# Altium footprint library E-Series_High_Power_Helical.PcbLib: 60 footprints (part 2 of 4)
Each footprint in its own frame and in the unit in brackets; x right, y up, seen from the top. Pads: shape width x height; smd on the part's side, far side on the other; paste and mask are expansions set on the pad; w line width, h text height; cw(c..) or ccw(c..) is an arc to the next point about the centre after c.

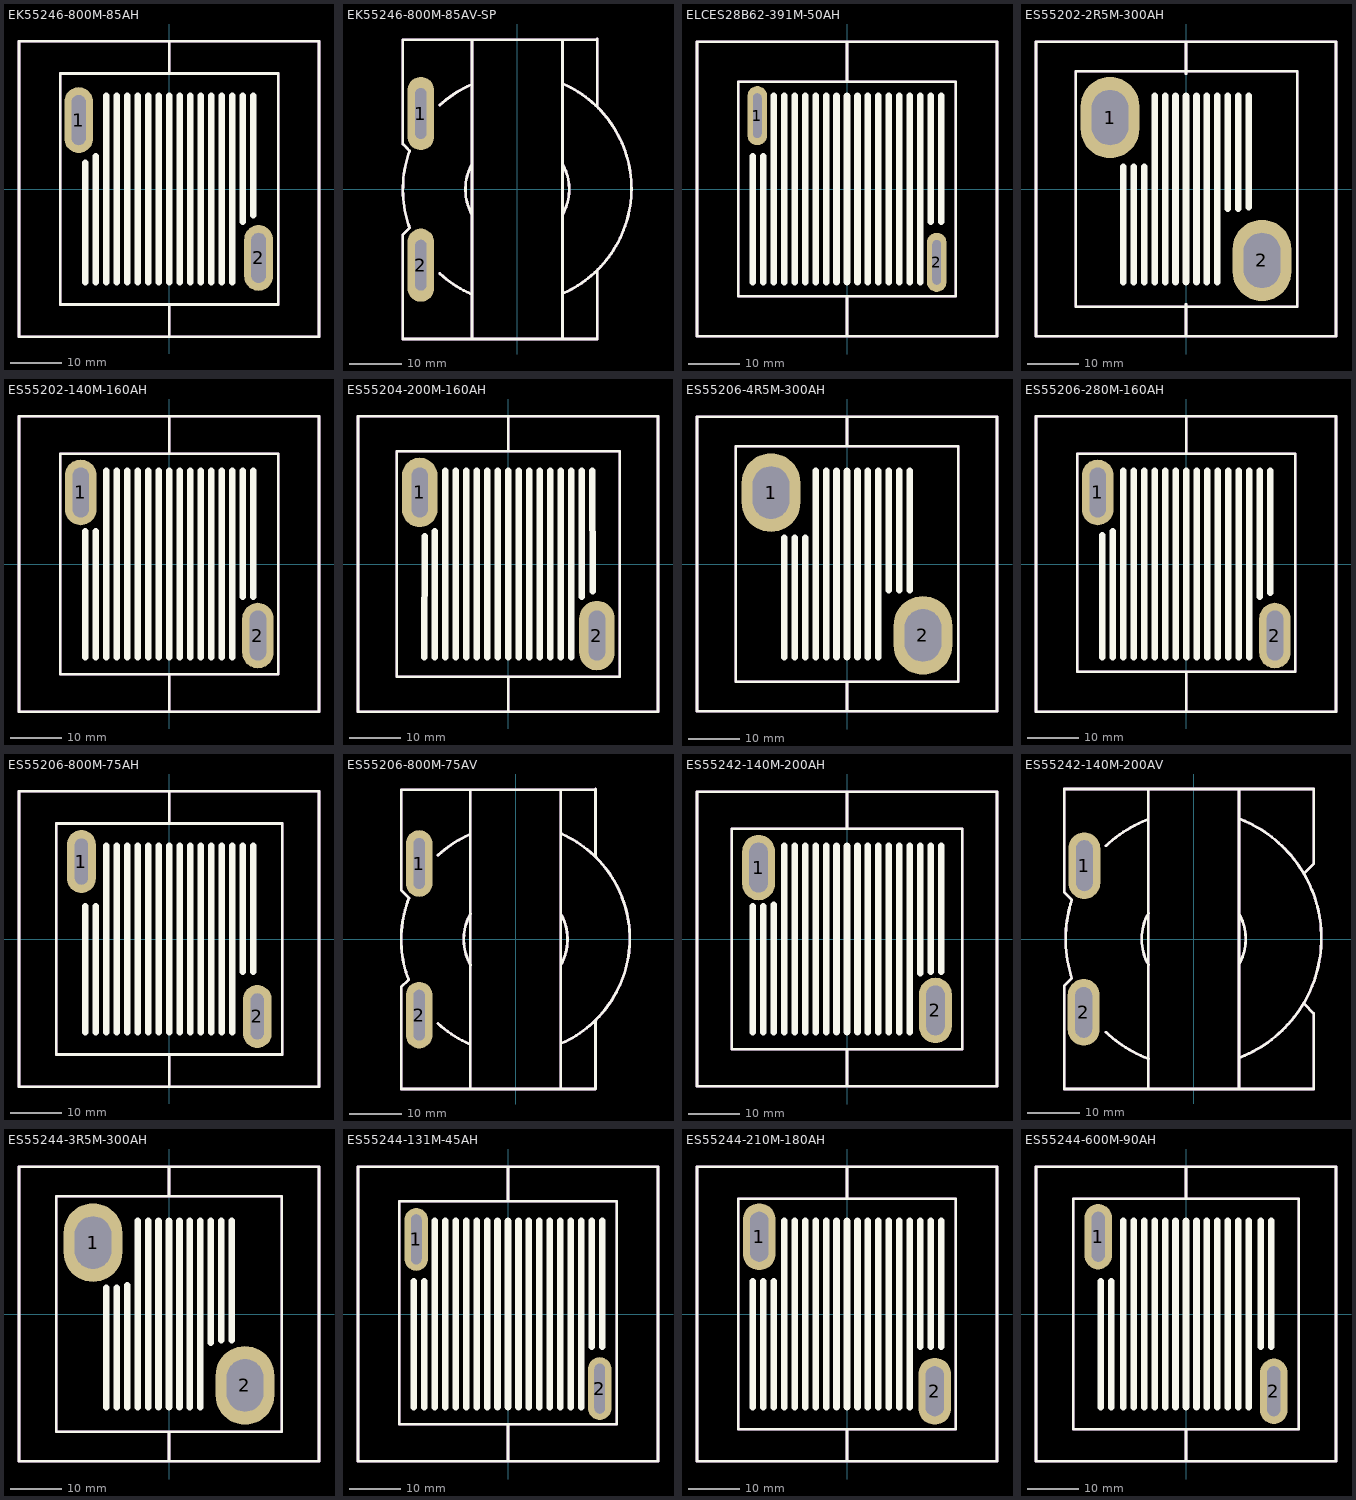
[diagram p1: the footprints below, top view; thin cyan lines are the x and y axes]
## EK55246-800M-85AH [mil]
pads (2):
  oval 220x500 hole 110 slot 380 at 90 deg: 1(-690,525) 2(680,-525)
Top Overlay:
  lines w19.68: 0,-1120 0,-880 ; 0,880 0,1120 ; -1145,-1125 1140,-1125 1140,1125 -1145,1125 -1145,-1125 ; -830,-880 -830,880 830,880 830,-880 -830,-880
  lines w50: -640,-710 -640,200 ; -560,-710 -560,250 ; -480,-710 -480,710 ; -400,-710 -400,710 ; -320,-710 -320,710 ; -240,-710 -240,710 ; -160,-710 -160,710 ; -80,-710 -80,710 ; 0,-710 0,710 ; 80,-710 80,710 ; 160,-710 160,710 ; 240,-710 240,710 ; 320,-710 320,710 ; 400,-710 400,710 ; 480,-710 480,710 ; 560,-250 560,710 ; 640,-200 640,710
Components Top Assy:
  lines w19.68: 0,-1120 0,-880 ; 0,880 0,1120 ; -1145,-1125 1140,-1125 1140,1125 -1145,1125 -1145,-1125 ; -830,-880 -830,880 830,880 830,-880 -830,-880
  text "'.Designator'" at -938.15,-44.83 h400

## EK55246-800M-85AV-SP [mil]
pads (2):
  oval 200x550 hole 85 slot 380 at 90 deg: 1(-725,570) 2(-725,-570)
Top Overlay:
  lines w19.68: -810,-290 -860,-340 -860,-1125 600,-1125 ; -810,290 -830,310 -860,340 -860,1125 590,1125
  lines w20: -813.86,-277.9 cw(c0,0) -809.67,289.88 ; -583.48,-632.1 ccw(c0,0) -344.8,-788.11 ; -583.48,632.1 cw(c0,0) -344.8,788.11 ; -340,-1120 -340,1110 ; -338.61,-193.49 cw(c0,0) -338.61,193.49 ; 338.61,-193.49 ccw(c0,0) 338.61,193.49 ; 340,-1110 340,1120 ; 342.28,-782.35 ccw(c-2.13,5.68) 346.4,791.89 ; 600,-1120 600,-608.95 ; 600,620 600,1130
Components Top Assy:
  lines w19.68: -810,-290 -860,-340 -860,-1125 600,-1125 ; -810,290 -830,310 -860,340 -860,1125 590,1125
  lines w20: -813.86,-277.9 cw(c0,0) -809.67,289.88 ; -583.48,-632.1 ccw(c0,0) -344.8,-788.11 ; -583.48,632.1 cw(c0,0) -344.8,788.11 ; -340,-1120 -340,1110 ; -338.61,-193.49 cw(c0,0) -338.61,193.49 ; 338.61,-193.49 ccw(c0,0) 338.61,193.49 ; 340,-1110 340,1120 ; 342.28,-782.35 ccw(c-2.13,5.68) 346.4,791.89 ; 600,-1120 600,-608.95 ; 600,620 600,1130
  text "'.Designator'" at -968.15,-74.83 h400

## ELCES28B62-391M-50AH [mil]
pads (2):
  oval 150x450 hole 65 slot 340 at 90 deg: 1(-685,560) 2(685,-560)
Top Overlay:
  lines w19.68: 0,-1120 0,-820 ; 0,820 0,1120 ; -1145,-1125 -1145,1125 1145,1125 1145,-1125 -1145,-1125 ; -830,-820 -830,820 830,820 830,-820 -830,-820
  lines w50: -720,-710 -720,250 ; -640,-710 -640,250 ; -560,-710 -560,710 ; -480,-710 -480,710 ; -400,-710 -400,710 ; -320,-710 -320,710 ; -240,-710 -240,710 ; -160,-710 -160,710 ; -80,-710 -80,710 ; 0,-710 0,710 ; 80,-710 80,710 ; 160,-710 160,710 ; 240,-710 240,710 ; 320,-710 320,710 ; 400,-710 400,710 ; 480,-710 480,710 ; 560,-710 560,710 ; 640,-250 640,710 ; 720,-250 720,710
Components Top Assy:
  lines w19.68: 0,-1120 0,-820 ; 0,820 0,1120 ; -1145,-1125 -1145,1125 1145,1125 1145,-1125 -1145,-1125 ; -830,-820 -830,820 830,820 830,-820 -830,-820
  text "'.Designator'" at -938.15,-44.83 h400

## ES55202-2R5M-300AH [mil]
pads (2):
  oval 450x620 hole 280 slot 420 at 90 deg: 1(-580,545) 2(580,-545)
Top Overlay:
  lines w19.68: 0,-1120 0,-880 ; 0,880 0,1120 ; -1145,-1125 -1145,1125 1145,1125 1145,-1125 -1145,-1125 ; -840,-900 -840,900 850,900 850,-900 -840,-900
  lines w50: -480,-710 -480,170 ; -400,-710 -400,170 ; -320,-710 -320,170 ; -240,-710 -240,710 ; -160,-710 -160,710 ; -80,-710 -80,710 ; 0,-710 0,710 ; 80,-710 80,710 ; 160,-710 160,710 ; 240,-710 240,710 ; 320,-150 320,710 ; 400,-150 400,710 ; 480,-140 480,710
Components Top Assy:
  lines w19.68: 0,-1120 0,-880 ; 0,880 0,1120 ; -1145,-1125 -1145,1125 1145,1125 1145,-1125 -1145,-1125 ; -840,-900 -840,900 850,900 850,-900 -840,-900
  text "'.Designator'" at -938.15,-44.83 h400

## ES55202-140M-160AH [mil]
pads (2):
  oval 240x500 hole 125 slot 380 at 90 deg: 1(-675,545) 2(675,-545)
Top Overlay:
  lines w19.68: 0,-1120 0,-840 ; 0,840 0,1120 ; -1145,-1125 -1145,1125 1140,1125 1140,-1125 -1145,-1125 ; -830,-840 -830,840 830,840 830,-840 -830,-840
  lines w50: -640,-710 -640,250 ; -560,-710 -560,250 ; -480,-710 -480,710 ; -400,-710 -400,710 ; -320,-710 -320,710 ; -240,-710 -240,710 ; -160,-710 -160,710 ; -80,-710 -80,710 ; 0,-710 0,710 ; 80,-710 80,710 ; 160,-710 160,710 ; 240,-710 240,710 ; 320,-710 320,710 ; 400,-710 400,710 ; 480,-710 480,710 ; 560,-250 560,710 ; 640,-250 640,710
Components Top Assy:
  lines w19.68: 0,-1120 0,-840 ; 0,840 0,1120 ; -1145,-1125 -1145,1125 1140,1125 1140,-1125 -1145,-1125 ; -830,-840 -830,840 830,840 830,-840 -830,-840
  text "'.Designator'" at -938.15,-44.83 h400

## ES55204-200M-160AH [mil]
pads (2):
  oval 270x530 hole 125 slot 380 at 90 deg: 1(-675,545) 2(675,-545)
Top Overlay:
  lines w19.68: 0,-1120 0,-860 ; 0,860 0,1120 ; -1145,-1125 -1145,1125 1140,1125 1140,-1125 -1145,-1125 ; -850,-860 -850,860 850,860 850,-860 -850,-860
  lines w50: -640,-710 -635,211 ; -560,-710 -560,250 ; -480,-710 -480,710 ; -400,-710 -400,710 ; -320,-710 -320,710 ; -240,-710 -240,710 ; -160,-710 -160,710 ; -80,-710 -80,710 ; 0,-710 0,710 ; 80,-710 80,710 ; 160,-710 160,710 ; 240,-710 240,710 ; 320,-710 320,710 ; 400,-710 400,710 ; 480,-710 480,710 ; 560,-250 560,710 ; 640,710 642,-209
Components Top Assy:
  lines w19.68: 0,-1120 0,-860 ; 0,860 0,1120 ; -1145,-1125 -1145,1125 1140,1125 1140,-1125 -1145,-1125 ; -850,-860 -850,860 850,860 850,-860 -850,-860
  text "'.Designator'" at -948.15,-44.83 h400

## ES55206-4R5M-300AH [mil]
pads (2):
  oval 450x600 hole 280 slot 400 at 90 deg: 1(-580,545) 2(580,-545)
Top Overlay:
  lines w19.68: 0,-1120 0,-900 ; 0,900 0,1120 ; -1145,-1125 -1145,1125 1145,1125 1145,-1125 -1145,-1125 ; -850,-900 -850,900 850,900 850,-900 -850,-900
  lines w50: -480,-710 -480,200 ; -400,-710 -400,200 ; -320,-710 -320,200 ; -240,-710 -240,710 ; -160,-710 -160,710 ; -80,-710 -80,710 ; 0,-710 0,710 ; 80,-710 80,710 ; 160,-710 160,710 ; 240,-710 240,710 ; 320,-200 320,710 ; 400,-200 400,710 ; 480,-200 480,710
Components Top Assy:
  lines w19.68: 0,-1120 0,-900 ; 0,900 0,1120 ; -1145,-1125 -1145,1125 1145,1125 1145,-1125 -1145,-1125 ; -850,-900 -850,900 850,900 850,-900 -850,-900
  text "'.Designator'" at -928.15,-104.83 h400

## ES55206-280M-160AH [mil]
pads (2):
  oval 240x500 hole 125 slot 380 at 90 deg: 1(-675,545) 2(675,-545)
Top Overlay:
  lines w19.68: 0,-1120 0,-820 ; 0,840 0,1120 ; -1145,-1125 1140,-1125 1140,1125 -1145,1125 -1145,-1125 ; -830,-820 830,-820 830,840 -830,840 -830,-820
  lines w50: -640,-710 -640,220 ; -560,-710 -560,250 ; -480,-710 -480,710 ; -400,-710 -400,710 ; -320,-710 -320,710 ; -240,-710 -240,710 ; -160,-710 -160,710 ; -80,-710 -80,710 ; 0,-710 0,710 ; 80,-710 80,710 ; 160,-710 160,710 ; 240,-710 240,710 ; 320,-710 320,710 ; 400,-710 400,710 ; 480,-710 480,710 ; 560,-250 560,710 ; 640,-220 640,710
Components Top Assy:
  lines w19.68: 0,-1120 0,-820 ; 0,840 0,1120 ; -1145,-1125 1140,-1125 1140,1125 -1145,1125 -1145,-1125 ; -830,-820 830,-820 830,840 -830,840 -830,-820
  text "'.Designator'" at -938.15,-44.83 h400

## ES55206-800M-75AH [mil]
pads (2):
  oval 220x480 hole 100 slot 350 at 90 deg: 1(-670,590) 2(670,-590)
Top Overlay:
  lines w19.68: 0,-1120 0,-880 ; 0,880 0,1120 ; -1145,-1125 -1145,1125 1140,1125 1140,-1125 -1145,-1125 ; -860,-880 860,-880 860,880 -860,880 -860,-880
  lines w50: -640,-710 -640,250 ; -560,-710 -560,250 ; -480,-710 -480,710 ; -400,-710 -400,710 ; -320,-710 -320,710 ; -240,-710 -240,710 ; -160,-710 -160,710 ; -80,-710 -80,710 ; 0,-710 0,710 ; 80,-710 80,710 ; 160,-710 160,710 ; 240,-710 240,710 ; 320,-710 320,710 ; 400,-710 400,710 ; 480,-710 480,710 ; 560,-250 560,710 ; 640,-250 640,710
Components Top Assy:
  lines w19.68: 0,-1120 0,-880 ; 0,880 0,1120 ; -1145,-1125 -1145,1125 1140,1125 1140,-1125 -1145,-1125 ; -860,-880 860,-880 860,880 -860,880 -860,-880
  text "'.Designator'" at -938.15,-44.83 h400

## ES55206-800M-75AV [mil]
pads (2):
  oval 200x500 hole 85 slot 380 at 90 deg: 1(-725,570) 2(-725,-570)
Top Overlay:
  lines w19.68: -804.35,-304.35 -860,-360 -860,-1125 600,-1125 ; -800,310 -860,370 -860,1125 590,1125
  lines w20: -804.35,-304.35 cw(c0,0) -801.9,310.74 ; -583.48,-632.1 ccw(c0,0) -344.8,-788.11 ; -583.48,632.1 cw(c0,0) -344.8,788.11 ; -340,-1120 -340,1110 ; -338.61,-193.49 cw(c0,0) -338.61,193.49 ; 338.61,-193.49 ccw(c0,0) 338.61,193.49 ; 340,-1110 340,1120 ; 342.28,-782.35 ccw(c-2.13,5.68) 346.4,791.89 ; 600,-1120 600,-608.95 ; 600,620 600,1130
Components Top Assy:
  lines w19.68: -804.35,-304.35 -860,-360 -860,-1125 600,-1125 ; -800,310 -860,370 -860,1125 590,1125
  lines w20: -804.35,-304.35 cw(c0,0) -801.9,310.74 ; -583.48,-632.1 ccw(c0,0) -344.8,-788.11 ; -583.48,632.1 cw(c0,0) -344.8,788.11 ; -340,-1120 -340,1110 ; -338.61,-193.49 cw(c0,0) -338.61,193.49 ; 338.61,-193.49 ccw(c0,0) 338.61,193.49 ; 340,-1110 340,1120 ; 342.28,-782.35 ccw(c-2.13,5.68) 346.4,791.89 ; 600,-1120 600,-608.95 ; 600,620 600,1130
  text "'.Designator'" at -968.15,-74.83 h400

## ES55242-140M-200AH [mil]
pads (2):
  oval 250x500 hole 140 slot 380 at 90 deg: 1(-675,545) 2(675,-545)
Top Overlay:
  lines w19.68: 0,-1120 0,-840 ; 0,840 0,1120 ; -1145,-1125 -1145,1125 1145,1125 1145,-1125 -1145,-1125 ; -880,-840 -880,840 880,840 880,-840 -880,-840
  lines w50: -720,-710 -720,250 ; -640,-710 -640,250 ; -560,-710 -560,260 ; -480,-710 -480,710 ; -400,-710 -400,710 ; -320,-710 -320,710 ; -240,-710 -240,710 ; -160,-710 -160,710 ; -80,-710 -80,710 ; 0,-710 0,710 ; 80,-710 80,710 ; 160,-710 160,710 ; 240,-710 240,710 ; 320,-710 320,710 ; 400,-710 400,710 ; 480,-710 480,710 ; 560,-260 560,710 ; 640,-250 640,710 ; 720,-250 720,710
Components Top Assy:
  lines w19.68: 0,-1120 0,-840 ; 0,840 0,1120 ; -1145,-1125 -1145,1125 1145,1125 1145,-1125 -1145,-1125 ; -880,-840 -880,840 880,840 880,-840 -880,-840
  text "'.Designator'" at -938.15,-44.83 h400

## ES55242-140M-200AV [mil]
pads (2):
  oval 240x500 hole 125 slot 380 at 90 deg: 1(-820,550) 2(-825,-550)
Top Overlay:
  lines w19.68: -915,-295 -970,-350 -970,-1125 900,-1125 ; -914.08,294.08 -970,350 -970,1125 900,1125
  lines w20: -917.16,-283.58 cw(c0,0) -913.74,294.43 ; -658.87,698.21 cw(c0,0) -347.95,894.72 ; -658.27,-698.77 ccw(c0,0) -339.26,-898.05 ; -340,-1120 -340,1110 ; -338.61,-193.49 cw(c0,0) -338.61,193.49 ; 338.61,-193.49 ccw(c0,0) 338.61,193.49 ; 340,-1110 340,1120 ; 352.55,-886.4 ccw(c-2.13,5.68) 353.01,897.57 ; 830,-488.75 900,-558.75 900,-1120 ; 830,493.75 900,563.75 900,1125
Components Top Assy:
  lines w19.68: -915,-295 -970,-350 -970,-1125 900,-1125 ; -914.08,294.08 -970,350 -970,1125 900,1125
  lines w20: -917.16,-283.58 cw(c0,0) -913.74,294.43 ; -658.87,698.21 cw(c0,0) -347.95,894.72 ; -658.27,-698.77 ccw(c0,0) -339.26,-898.05 ; -340,-1120 -340,1110 ; -338.61,-193.49 cw(c0,0) -338.61,193.49 ; 338.61,-193.49 ccw(c0,0) 338.61,193.49 ; 340,-1110 340,1120 ; 352.55,-886.4 ccw(c-2.13,5.68) 353.01,897.57 ; 830,-488.75 900,-558.75 900,-1120 ; 830,493.75 900,563.75 900,1125
  text "'.Designator'" at -918.15,-54.83 h400

## ES55244-3R5M-300AH [mil]
pads (2):
  oval 450x600 hole 280 slot 400 at 90 deg: 1(-580,545) 2(580,-545)
Top Overlay:
  lines w19.68: 0,-1125 0,-900 ; 0,900 0,1120 ; -1145,-1125 1145,-1125 1145,1125 -1145,1125 -1145,-1125 ; -860,-900 860,-900 860,900 -860,900 -860,-900
  lines w50: -480,-710 -480,200 ; -400,-710 -400,200 ; -320,-710 -320,220 ; -240,-710 -240,710 ; -160,-710 -160,710 ; -80,-710 -80,710 ; 0,-710 0,710 ; 80,-710 80,710 ; 160,-710 160,710 ; 240,-710 240,710 ; 320,-220 320,710 ; 400,-200 400,710 ; 480,-200 480,710
Components Top Assy:
  lines w19.68: 0,-1120 0,-900 ; 0,900 0,1120 ; -1145,-1125 1145,-1125 1145,1125 -1145,1125 -1145,-1125 ; -860,-900 860,-900 860,900 -860,900 -860,-900
  text "'.Designator'" at -938.15,-44.83 h400

## ES55244-131M-45AH [mil]
pads (2):
  oval 180x480 hole 80 slot 380 at 90 deg: 1(-700,570) 2(700,-570)
Top Overlay:
  lines w19.68: 0,-1120 0,-840 ; 0,860 0,1120 ; -1145,-1125 -1145,1125 1145,1125 1145,-1125 -1145,-1125 ; -830,-840 -830,860 830,860 830,-840 -830,-840
  lines w50: -720,-710 -720,250 ; -640,-710 -640,250 ; -560,-710 -560,710 ; -480,-710 -480,710 ; -400,-710 -400,710 ; -320,-710 -320,710 ; -240,-710 -240,710 ; -160,-710 -160,710 ; -80,-710 -80,710 ; 0,-710 0,710 ; 80,-710 80,710 ; 160,-710 160,710 ; 240,-710 240,710 ; 320,-710 320,710 ; 400,-710 400,710 ; 480,-710 480,710 ; 560,-710 560,710 ; 640,-250 640,710 ; 720,-250 720,710
Components Top Assy:
  lines w19.68: 0,-1120 0,-840 ; 0,860 0,1120 ; -1145,-1125 -1145,1125 1145,1125 1145,-1125 -1145,-1125 ; -830,-840 -830,860 830,860 830,-840 -830,-840
  text "'.Designator'" at -938.15,-44.83 h400

## ES55244-210M-180AH [mil]
pads (2):
  oval 250x510 hole 140 slot 380 at 90 deg: 1(-670,590) 2(670,-590)
Top Overlay:
  lines w19.68: 0,-1120 0,-880 ; 0,880 0,1120 ; -1145,-1125 -1145,1125 1145,1125 1145,-1125 -1145,-1125 ; -830,-880 -830,880 830,880 830,-880 -830,-880
  lines w50: -720,-710 -720,250 ; -640,-710 -640,250 ; -560,-710 -560,250 ; -480,-710 -480,710 ; -400,-710 -400,710 ; -320,-710 -320,710 ; -240,-710 -240,710 ; -160,-710 -160,710 ; -80,-710 -80,710 ; 0,-710 0,710 ; 80,-710 80,710 ; 160,-710 160,710 ; 240,-710 240,710 ; 320,-710 320,710 ; 400,-710 400,710 ; 480,-710 480,710 ; 560,-250 560,710 ; 640,-250 640,710 ; 720,-250 720,710
Components Top Assy:
  lines w19.68: 0,-1120 0,-880 ; 0,880 0,1120 ; -1145,-1125 -1145,1125 1145,1125 1145,-1125 -1145,-1125 ; -830,-880 -830,880 830,880 830,-880 -830,-880
  text "'.Designator'" at -938.15,-44.83 h400

## ES55244-600M-90AH [mil]
pads (2):
  oval 210x500 hole 100 slot 380 at 90 deg: 1(-670,590) 2(670,-590)
Top Overlay:
  lines w19.68: 0,-1120 0,-880 ; 0,880 0,1120 ; -1145,-1125 1145,-1125 1145,1125 -1145,1125 -1145,-1125 ; -860,-880 860,-880 860,880 -860,880 -860,-880
  lines w50: -650,-710 -650,250 ; -570,-710 -570,250 ; -480,-710 -480,710 ; -400,-710 -400,710 ; -320,-710 -320,710 ; -240,-710 -240,710 ; -160,-710 -160,710 ; -80,-710 -80,710 ; 0,-710 0,710 ; 80,-710 80,710 ; 160,-710 160,710 ; 240,-710 240,710 ; 320,-710 320,710 ; 400,-710 400,710 ; 480,-710 480,710 ; 570,-250 570,710 ; 650,-250 650,710
Components Top Assy:
  lines w19.68: 0,-1120 0,-880 ; 0,880 0,1120 ; -1145,-1125 1145,-1125 1145,1125 -1145,1125 -1145,-1125 ; -860,-880 860,-880 860,880 -860,880 -860,-880
  text "'.Designator'" at -938.15,-44.83 h400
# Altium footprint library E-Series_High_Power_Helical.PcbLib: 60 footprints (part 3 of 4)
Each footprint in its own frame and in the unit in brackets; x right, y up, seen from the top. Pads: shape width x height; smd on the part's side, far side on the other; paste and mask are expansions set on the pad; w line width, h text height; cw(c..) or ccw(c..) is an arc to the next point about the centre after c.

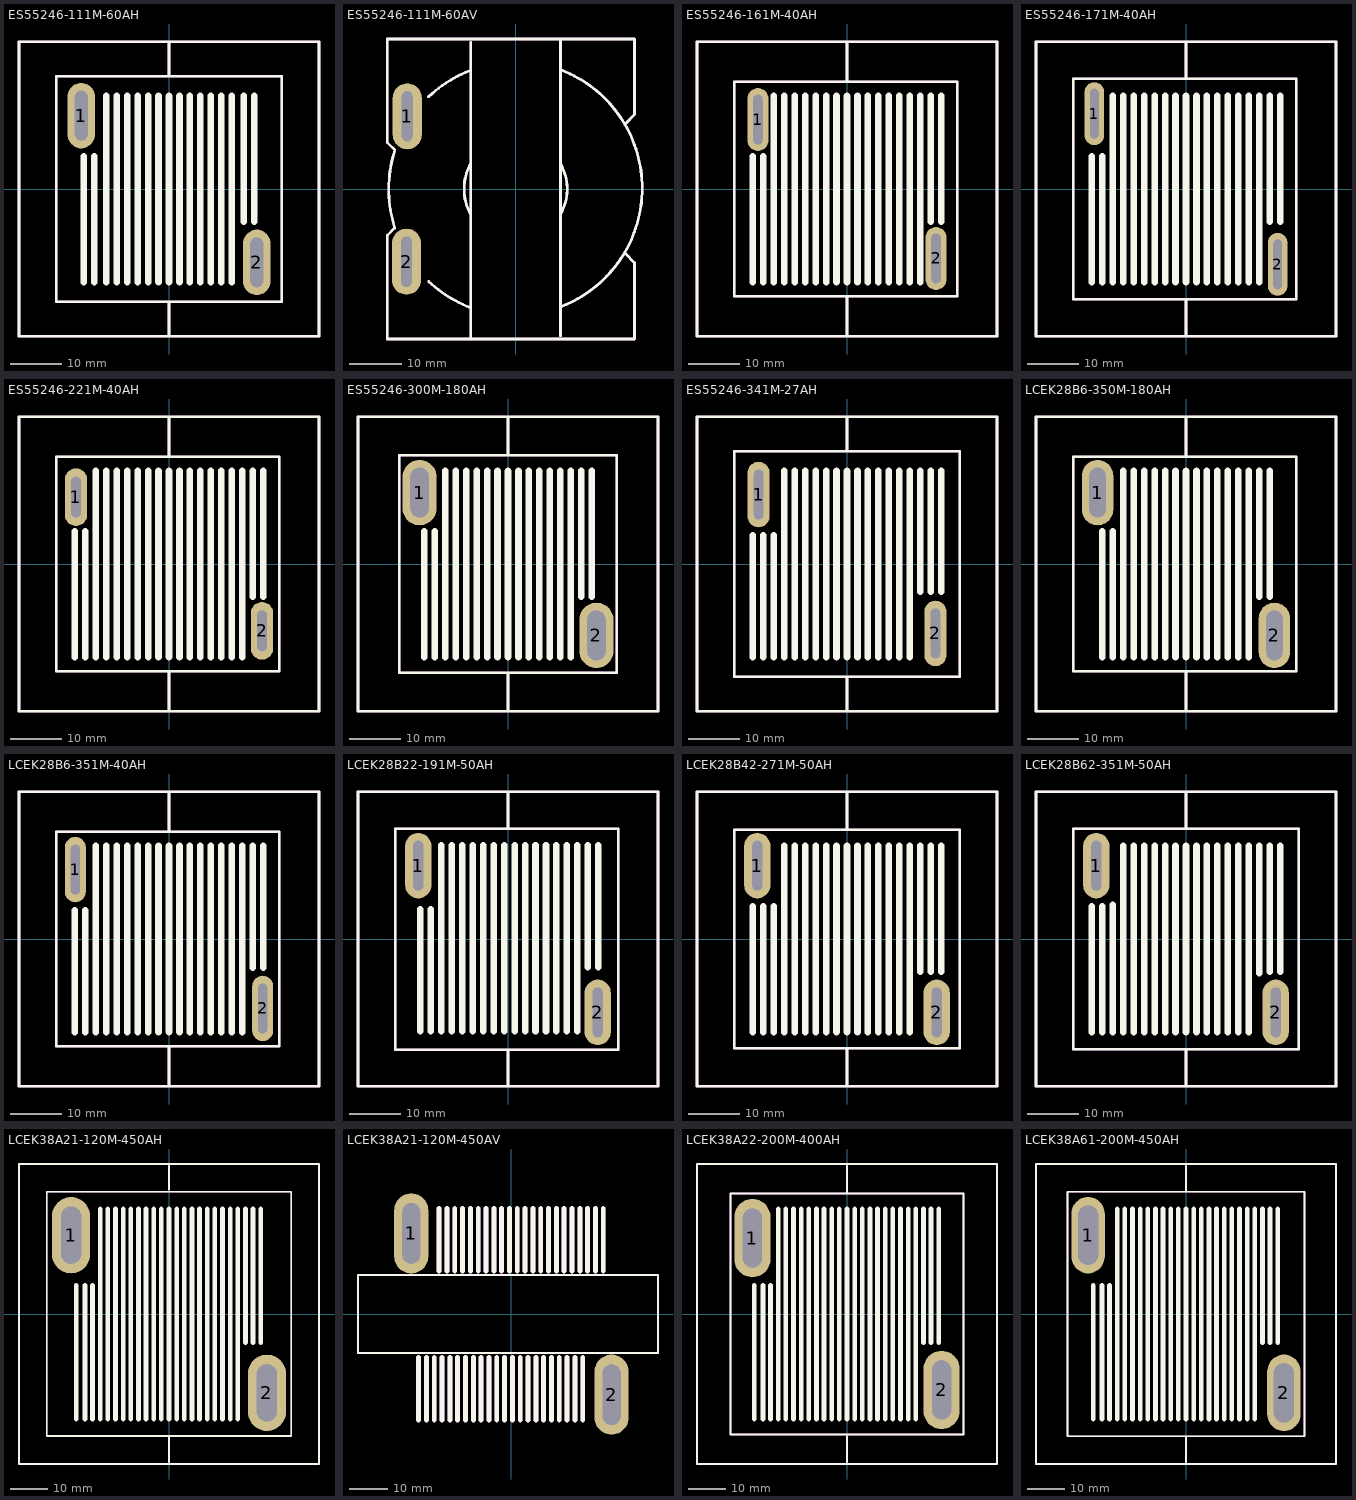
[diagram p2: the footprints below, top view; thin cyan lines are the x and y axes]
## ES55246-111M-60AH [mil]
pads (2):
  oval 210x500 hole 100 slot 380 at 90 deg: 1(-670,560) 2(670,-560)
Top Overlay:
  lines w19.68: 0,-1120 0,-860 ; 0,860 0,1120 ; -1145,-1125 -1145,1125 1145,1125 1145,-1125 -1145,-1125 ; -860,-860 -860,860 860,860 860,-860 -860,-860
  lines w50: -650,-710 -650,250 ; -570,-710 -570,250 ; -480,-710 -480,710 ; -400,-710 -400,710 ; -320,-710 -320,710 ; -240,-710 -240,710 ; -160,-710 -160,710 ; -80,-710 -80,710 ; 0,-710 0,710 ; 80,-710 80,710 ; 160,-710 160,710 ; 240,-710 240,710 ; 320,-710 320,710 ; 400,-710 400,710 ; 480,-710 480,710 ; 570,-250 570,710 ; 650,-250 650,710
Components Top Assy:
  lines w19.68: 0,-1120 0,-860 ; 0,860 0,1120 ; -1145,-1125 -1145,1125 1145,1125 1145,-1125 -1145,-1125 ; -860,-860 -860,860 860,860 860,-860 -860,-860
  text "'.Designator'" at -938.15,-44.83 h400

## ES55246-111M-60AV [mil]
pads (2):
  oval 220x500 hole 80 slot 380 at 90 deg: 1(-820,550) 2(-825,-550)
Top Overlay:
  lines w19.68: -915,-295 -970,-350 -970,-1135 900,-1135 ; -914.08,294.08 -970,350 -970,1135 900,1135
  lines w20: -917.16,-283.58 cw(c0,0) -913.74,294.43 ; -658.87,698.21 cw(c0,0) -347.95,894.72 ; -658.27,-698.77 ccw(c0,0) -339.26,-898.05 ; -340,-1120 -340,1110 ; -338.61,-193.49 cw(c0,0) -338.61,193.49 ; 338.61,-193.49 ccw(c0,0) 338.61,193.49 ; 340,-1110 340,1120 ; 352.55,-886.4 ccw(c-2.13,5.68) 353.01,897.57 ; 830,-488.75 900,-558.75 900,-1135 ; 830,493.75 900,563.75 900,1135
Components Top Assy:
  lines w19.68: -915,-295 -970,-350 -970,-1135 900,-1135 ; -914.08,294.08 -970,350 -970,1135 900,1135
  lines w20: -917.16,-283.58 cw(c0,0) -913.74,294.43 ; -658.87,698.21 cw(c0,0) -347.95,894.72 ; -658.27,-698.77 ccw(c0,0) -339.26,-898.05 ; -340,-1120 -340,1110 ; -338.61,-193.49 cw(c0,0) -338.61,193.49 ; 338.61,-193.49 ccw(c0,0) 338.61,193.49 ; 340,-1110 340,1120 ; 352.55,-886.4 ccw(c-2.13,5.68) 353.01,897.57 ; 830,-488.75 900,-558.75 900,-1135 ; 830,493.75 900,563.75 900,1135
  text "'.Designator'" at -918.15,-54.83 h400

## ES55246-161M-40AH [mil]
pads (2):
  oval 160x480 hole 70 slot 380 at 90 deg: 1(-680,530) 2(680,-530)
Top Overlay:
  lines w19.68: 0,-1120 0,-820 ; 0,820 0,1120 ; -1145,-1125 1145,-1125 1145,1125 -1145,1125 -1145,-1125 ; -860,-820 840,-820 840,820 -860,820 -860,-820
  lines w50: -720,-710 -720,250 ; -640,-710 -640,250 ; -560,-710 -560,710 ; -480,-710 -480,710 ; -400,-710 -400,710 ; -320,-710 -320,710 ; -240,-710 -240,710 ; -160,-710 -160,710 ; -80,-710 -80,710 ; 0,-710 0,710 ; 80,-710 80,710 ; 160,-710 160,710 ; 240,-710 240,710 ; 320,-710 320,710 ; 400,-710 400,710 ; 480,-710 480,710 ; 560,-710 560,710 ; 640,-250 640,710 ; 720,-250 720,710
Components Top Assy:
  lines w19.68: 0,-1120 0,-820 ; 0,820 0,1120 ; -1145,-1125 -1145,1125 1145,1125 1145,-1125 -1145,-1125 ; -860,-820 -860,820 840,820 840,-820 -860,-820
  text "'.Designator'" at -938.15,-44.83 h400

## ES55246-171M-40AH [mil]
pads (2):
  oval 150x480 hole 65 slot 380 at 90 deg: 1(-700,575) 2(700,-575)
Top Overlay:
  lines w19.68: 0,-1120 0,-840 ; 0,840 0,1120 ; -1145,-1125 -1145,1125 1145,1125 1145,-1125 -1145,-1125 ; -860,-840 -860,840 840,840 840,-840 -860,-840
  lines w50: -720,-710 -720,250 ; -640,-710 -640,250 ; -560,-710 -560,710 ; -480,-710 -480,710 ; -400,-710 -400,710 ; -320,-710 -320,710 ; -240,-710 -240,710 ; -160,-710 -160,710 ; -80,-710 -80,710 ; 0,-710 0,710 ; 80,-710 80,710 ; 160,-710 160,710 ; 240,-710 240,710 ; 320,-710 320,710 ; 400,-710 400,710 ; 480,-710 480,710 ; 560,-710 560,710 ; 640,-250 640,710 ; 720,-250 720,710
Components Top Assy:
  lines w19.68: 0,-1120 0,-850 ; 0,840 0,1120 ; -1145,-1125 -1145,1125 1145,1125 1145,-1125 -1145,-1125 ; -860,-840 -860,840 840,840 840,-840 -860,-840
  text "'.Designator'" at -938.15,-44.83 h400

## ES55246-221M-40AH [mil]
pads (2):
  oval 170x440 hole 75 slot 310 at 90 deg: 1(-710,510) 2(710,-510)
Top Overlay:
  lines w19.68: 0,-1120 0,-820 ; 0,820 0,1120 ; -1145,-1125 1145,-1125 1145,1125 -1145,1125 -1145,-1125 ; -860,-820 840,-820 840,820 -860,820 -860,-820
  lines w50: -720,-710 -720,250 ; -640,-710 -640,250 ; -560,-710 -560,710 ; -480,-710 -480,710 ; -400,-710 -400,710 ; -320,-710 -320,710 ; -240,-710 -240,710 ; -160,-710 -160,710 ; -80,-710 -80,710 ; 0,-710 0,710 ; 80,-710 80,710 ; 160,-710 160,710 ; 240,-710 240,710 ; 320,-710 320,710 ; 400,-710 400,710 ; 480,-710 480,710 ; 560,-710 560,710 ; 640,-250 640,710 ; 720,-250 720,710
Components Top Assy:
  lines w19.68: 0,-1120 0,-820 ; 0,820 0,1120 ; -1145,-1125 1145,-1125 1145,1125 -1145,1125 -1145,-1125 ; -860,-820 840,-820 840,820 -860,820 -860,-820
  text "'.Designator'" at -938.15,-44.83 h400

## ES55246-300M-180AH [mil]
pads (2):
  oval 260x500 hole 140 slot 380 at 90 deg: 1(-675,545) 2(675,-545)
Top Overlay:
  lines w19.68: 0,-1120 0,-840 ; 0,830 0,1120 ; -1145,-1125 1145,-1125 1145,1125 -1145,1125 -1145,-1125 ; -830,-830 830,-830 830,830 -830,830 -830,-830
  lines w50: -640,-710 -640,250 ; -560,-710 -560,250 ; -480,-710 -480,710 ; -400,-710 -400,710 ; -320,-710 -320,710 ; -240,-710 -240,710 ; -160,-710 -160,710 ; -80,-710 -80,710 ; 0,-710 0,710 ; 80,-710 80,710 ; 160,-710 160,710 ; 240,-710 240,710 ; 320,-710 320,710 ; 400,-710 400,710 ; 480,-710 480,710 ; 560,-250 560,710 ; 640,-250 640,710
Components Top Assy:
  lines w19.68: 0,-1120 0,-840 ; 0,830 0,1120 ; -1145,-1125 1145,-1125 1145,1125 -1145,1125 -1145,-1125 ; -830,-830 830,-830 830,830 -830,830 -830,-830
  text "'.Designator'" at -938.15,-44.83 h400

## ES55246-341M-27AH [mil]
pads (2):
  oval 170x500 hole 70 slot 380 at 90 deg: 1(-675,530) 2(675,-530)
Top Overlay:
  lines w19.68: 0,-1120 0,-860 ; 0,860 0,1120 ; -1145,-1125 -1145,1125 1145,1125 1145,-1125 -1145,-1125 ; -860,-860 -860,860 860,860 860,-860 -860,-860
  lines w50: -720,-710 -720,220 ; -640,-710 -640,220 ; -560,-710 -560,220 ; -480,-710 -480,710 ; -400,-710 -400,710 ; -320,-710 -320,710 ; -240,-710 -240,710 ; -160,-710 -160,710 ; -80,-710 -80,710 ; 0,-710 0,710 ; 80,-710 80,710 ; 160,-710 160,710 ; 240,-710 240,710 ; 320,-710 320,710 ; 400,-710 400,710 ; 480,-710 480,710 ; 560,-210 560,710 ; 640,-210 640,710 ; 720,-210 720,710
Components Top Assy:
  lines w19.68: 0,-1120 0,-860 ; 0,860 0,1120 ; -1145,-1125 -1145,1125 1145,1125 1145,-1125 -1145,-1125 ; -860,-860 -860,860 860,860 860,-860 -860,-860
  text "'.Designator'" at -938.15,-44.83 h400

## LCEK28B6-350M-180AH [mil]
pads (2):
  oval 240x500 hole 125 slot 380 at 90 deg: 1(-675,545) 2(675,-545)
Top Overlay:
  lines w19.68: 0,-1120 0,-820 ; 0,820 0,1120 ; -1145,-1125 -1145,1125 1145,1125 1145,-1125 -1145,-1125 ; -860,-820 -860,820 840,820 840,-820 -860,-820
  lines w50: -640,-710 -640,250 ; -560,-710 -560,250 ; -480,-710 -480,710 ; -400,-710 -400,710 ; -320,-710 -320,710 ; -240,-710 -240,710 ; -160,-710 -160,710 ; -80,-710 -80,710 ; 0,-710 0,710 ; 80,-710 80,710 ; 160,-710 160,710 ; 240,-710 240,710 ; 320,-710 320,710 ; 400,-710 400,710 ; 480,-710 480,710 ; 560,-250 560,710 ; 640,-250 640,710
Components Top Assy:
  lines w19.68: 0,-1120 0,-820 ; 0,820 0,1120 ; -1145,-1125 -1145,1125 1145,1125 1145,-1125 -1145,-1125 ; -860,-820 -860,820 840,820 840,-820 -860,-820
  text "'.Designator'" at -938.15,-44.83 h400

## LCEK28B6-351M-40AH [mil]
pads (2):
  oval 160x500 hole 70 slot 380 at 90 deg: 1(-715,530) 2(715,-530)
Top Overlay:
  lines w19.68: 0,-1120 0,-820 ; 0,820 0,1120 ; -1145,-1125 -1145,1125 1145,1125 1145,-1125 -1145,-1125 ; -860,-820 -860,820 840,820 840,-820 -860,-820
  lines w50: -720,-710 -720,220 ; -640,-710 -640,220 ; -560,-710 -560,710 ; -480,-710 -480,710 ; -400,-710 -400,710 ; -320,-710 -320,710 ; -240,-710 -240,710 ; -160,-710 -160,710 ; -80,-710 -80,710 ; 0,-710 0,710 ; 80,-710 80,710 ; 160,-710 160,710 ; 240,-710 240,710 ; 320,-710 320,710 ; 400,-710 400,710 ; 480,-710 480,710 ; 560,-710 560,710 ; 640,-220 640,710 ; 720,-220 720,710
Components Top Assy:
  lines w19.68: 0,-1120 0,-820 ; 0,820 0,1120 ; -1145,-1125 -1145,1125 1145,1125 1145,-1125 -1145,-1125 ; -860,-820 -860,820 840,820 840,-820 -860,-820
  text "'.Designator'" at -938.15,-44.83 h400

## LCEK28B22-191M-50AH [mil]
pads (2):
  oval 200x500 hole 75 slot 380 at 90 deg: 1(-685,560) 2(685,-560)
Top Overlay:
  lines w19.68: 0,-1120 0,-855 ; 0,850 0,1120 ; -1145,-1125 -1145,1125 1145,1125 1145,-1125 -1145,-1125 ; -860,-845 -860,840 840,840 840,-845 -860,-845
  lines w50: -670,-705 -670,225 ; -590,-705 -590,225 ; -510,-705 -510,715 ; -430,-705 -430,715 ; -350,-705 -350,715 ; -270,-705 -270,715 ; -190,-705 -190,715 ; -110,-705 -110,715 ; -30,-705 -30,715 ; 50,-705 50,715 ; 130,-705 130,715 ; 210,-705 210,715 ; 290,-705 290,715 ; 370,-705 370,715 ; 450,-705 450,715 ; 530,-705 530,715 ; 610,-215 610,715 ; 690,-215 690,715
Components Top Assy:
  lines w19.68: 0,-1120 0,-855 ; 0,850 0,1120 ; -1145,-1125 -1145,1125 1145,1125 1145,-1125 -1145,-1125 ; -860,-845 -860,840 840,840 840,-845 -860,-845
  text "'.Designator'" at -938.15,-34.83 h400

## LCEK28B42-271M-50AH [mil]
pads (2):
  oval 200x500 hole 75 slot 380 at 90 deg: 1(-685,560) 2(685,-560)
Top Overlay:
  lines w19.68: 0,-1120 0,-835 ; 0,835 0,1120 ; -1145,-1125 -1145,1125 1145,1125 1145,-1125 -1145,-1125 ; -860,-835 -860,835 860,835 860,-835 -860,-835
  lines w50: -720,-710 -720,250 ; -640,-710 -640,250 ; -560,-710 -560,250 ; -480,-710 -480,710 ; -400,-710 -400,710 ; -320,-710 -320,710 ; -240,-710 -240,710 ; -160,-710 -160,710 ; -80,-710 -80,710 ; 0,-710 0,710 ; 80,-710 80,710 ; 160,-710 160,710 ; 240,-710 240,710 ; 320,-710 320,710 ; 400,-710 400,710 ; 480,-710 480,710 ; 560,-250 560,710 ; 640,-250 640,710 ; 720,-250 720,710
Components Top Assy:
  lines w19.68: 0,-1120 0,-840 ; 0,835 0,1120 ; -1145,-1125 -1145,1125 1145,1125 1145,-1125 -1145,-1125 ; -860,-835 -860,835 860,835 860,-835 -860,-835
  text "'.Designator'" at -938.15,-44.83 h400

## LCEK28B62-351M-50AH [mil]
pads (2):
  oval 200x500 hole 75 slot 380 at 90 deg: 1(-685,560) 2(685,-560)
Top Overlay:
  lines w19.68: 0,-1120 0,-840 ; 0,840 0,1120 ; -1145,-1125 -1145,1125 1145,1125 1145,-1125 -1145,-1125 ; -860,-840 -860,840 860,840 860,-840 -860,-840
  lines w50: -720,-710 -720,250 ; -640,-710 -640,250 ; -560,-710 -560,260 ; -480,-710 -480,710 ; -400,-710 -400,710 ; -320,-710 -320,710 ; -240,-710 -240,710 ; -160,-710 -160,710 ; -80,-710 -80,710 ; 0,-710 0,710 ; 80,-710 80,710 ; 160,-710 160,710 ; 240,-710 240,710 ; 320,-710 320,710 ; 400,-710 400,710 ; 480,-710 480,710 ; 560,-260 560,710 ; 640,-250 640,710 ; 720,-250 720,710
Components Top Assy:
  lines w19.68: 0,-1120 0,-840 ; 0,840 0,1120 ; -1145,-1125 -1145,1125 1145,1125 1145,-1125 -1145,-1125 ; -860,-840 -860,840 860,840 860,-840 -860,-840
  text "'.Designator'" at -938.15,-44.83 h400

## LCEK38A21-120M-450AH [mil]
pads (2):
  oval 400x800 hole 210 slot 600 at 90 deg: 1(-1025,825) 2(1025,-825)
Top Overlay:
  lines w19.68: 0,-1550 0,-1280 ; 0,1300 0,1550 ; -1570,-1570 1570,-1570 1570,1570 -1570,1570 -1570,-1570 ; -1280,-1275 1280,-1275 1280,1280 -1280,1280 -1280,-1275
  lines w50: -970,-1100 -970,300 ; -880,-1100 -880,300 ; -800,-1100 -800,300 ; -720,-1100 -720,1100 ; -640,-1100 -640,1100 ; -560,-1100 -560,1100 ; -480,-1100 -480,1100 ; -400,-1100 -400,1100 ; -320,-1100 -320,1100 ; -240,-1100 -240,1100 ; -160,-1100 -160,1100 ; -80,-1100 -80,1100 ; 0,-1100 0,1100 ; 80,-1100 80,1100 ; 160,-1100 160,1100 ; 240,-1100 240,1100 ; 320,-1100 320,1100 ; 400,-1100 400,1100 ; 480,-1100 480,1100 ; 560,-1100 560,1100 ; 640,-1100 640,1100 ; 720,-1100 720,1100 ; 800,-300 800,1100 ; 880,-300 880,1100 ; 960,-300 960,1100
Components Top Assy:
  lines w19.68: 0,-1550 0,-1280 ; 0,1300 0,1550 ; -1570,-1570 1570,-1570 1570,1570 -1570,1570 -1570,-1570 ; -1280,-1275 1280,-1275 1280,1280 -1280,1280 -1280,-1275
  text "'.Designator'" at -938.15,-44.83 h400

## LCEK38A21-120M-450AV [mil]
pads (2):
  oval 350x820 hole 185 slot 620 at 90 deg: 1(-1025,825) 2(1025,-825)
Top Overlay:
  lines w19.68: -1570,-400 -1570,400 1500,400 1500,-400 -1570,-400
  lines w50: -950,-1085 -950,-445 ; -870,-1085 -870,-445 ; -790,-1085 -790,-445 ; -740,440 -740,1080 ; -710,-1085 -710,-445 ; -660,440 -660,1080 ; -630,-1085 -630,-445 ; -580,440 -580,1080 ; -550,-1085 -550,-445 ; -500,440 -500,1080 ; -470,-1085 -470,-445 ; -420,440 -420,1080 ; -390,-1085 -390,-445 ; -340,440 -340,1080 ; -310,-1085 -310,-445 ; -260,440 -260,1080 ; -230,-1085 -230,-445 ; -180,440 -180,1080 ; -150,-1085 -150,-445 ; -100,440 -100,1080 ; -70,-1085 -70,-445 ; -20,440 -20,1080 ; 10,-1085 10,-445 ; 60,440 60,1080 ; 90,-1085 90,-445 ; 140,440 140,1080 ; 170,-1085 170,-445 ; 220,440 220,1080 ; 250,-1085 250,-445 ; 300,440 300,1080 ; 330,-1085 330,-445 ; 380,440 380,1080 ; 410,-1085 410,-445 ; 460,440 460,1080 ; 490,-1085 490,-445 ; 540,440 540,1080 ; 570,-1085 570,-445 ; 620,440 620,1080 ; 650,-1085 650,-445 ; 700,440 700,1080 ; 730,-1085 730,-445 ; 780,440 780,1080 ; 860,440 860,1080 ; 940,440 940,1080
Components Top Assy:
  lines w19.68: -1570,-400 -1570,400 1500,400 1500,-400 -1570,-400
  lines w50: -950,-1085 -950,-445 ; -870,-1085 -870,-445 ; -790,-1085 -790,-445 ; -740,440 -740,1080 ; -710,-1085 -710,-445 ; -660,440 -660,1080 ; -630,-1085 -630,-445 ; -580,440 -580,1080 ; -550,-1085 -550,-445 ; -500,440 -500,1080 ; -470,-1085 -470,-445 ; -420,440 -420,1080 ; -390,-1085 -390,-445 ; -340,440 -340,1080 ; -310,-1085 -310,-445 ; -260,440 -260,1080 ; -230,-1085 -230,-445 ; -180,440 -180,1080 ; -150,-1085 -150,-445 ; -100,440 -100,1080 ; -70,-1085 -70,-445 ; -20,440 -20,1080 ; 10,-1085 10,-445 ; 60,440 60,1080 ; 90,-1085 90,-445 ; 140,440 140,1080 ; 170,-1085 170,-445 ; 220,440 220,1080 ; 250,-1085 250,-445 ; 300,440 300,1080 ; 330,-1085 330,-445 ; 380,440 380,1080 ; 410,-1085 410,-445 ; 460,440 460,1080 ; 490,-1085 490,-445 ; 540,440 540,1080 ; 570,-1085 570,-445 ; 620,440 620,1080 ; 650,-1085 650,-445 ; 700,440 700,1080 ; 730,-1085 730,-445 ; 780,440 780,1080 ; 860,440 860,1080 ; 940,440 940,1080
  text "'.Designator'" at -988.15,-69.83 h400

## LCEK38A22-200M-400AH [mil]
pads (2):
  oval 380x820 hole 200 slot 620 at 90 deg: 1(-990,795) 2(990,-795)
Top Overlay:
  lines w19.68: 0,-1550 0,-1280 ; 0,1260 0,1550 ; -1570,-1570 1570,-1570 1570,1570 -1570,1570 -1570,-1570 ; -1220,-1260 1220,-1260 1220,1260 -1220,1260 -1220,-1260
  lines w50: -970,-1100 -970,300 ; -880,-1100 -880,300 ; -800,-1100 -800,300 ; -720,-1100 -720,1100 ; -640,-1100 -640,1100 ; -560,-1100 -560,1100 ; -480,-1100 -480,1100 ; -400,-1100 -400,1100 ; -320,-1100 -320,1100 ; -240,-1100 -240,1100 ; -160,-1100 -160,1100 ; -80,-1100 -80,1100 ; 0,-1100 0,1100 ; 80,-1100 80,1100 ; 160,-1100 160,1100 ; 240,-1100 240,1100 ; 320,-1100 320,1100 ; 400,-1100 400,1100 ; 480,-1100 480,1100 ; 560,-1100 560,1100 ; 640,-1100 640,1100 ; 720,-1100 720,1100 ; 800,-300 800,1100 ; 880,-300 880,1100 ; 960,-300 960,1100
Components Top Assy:
  lines w19.68: 0,-1550 0,-1280 ; 0,1260 0,1550 ; -1570,-1570 -1570,1570 1570,1570 1570,-1570 -1570,-1570 ; -1220,-1260 -1220,1260 1220,1260 1220,-1260 -1220,-1260
  text "'.Designator'" at -938.15,-44.83 h400

## LCEK38A61-200M-450AH [mil]
pads (2):
  oval 350x800 hole 210 slot 620 at 90 deg: 1(-1025,825) 2(1025,-825)
Top Overlay:
  lines w19.68: 0,-1550 0,-1280 ; 0,1280 0,1550 ; -1570,-1570 1570,-1570 1570,1570 -1570,1570 -1570,-1570 ; -1240,-1280 1240,-1280 1240,1280 -1240,1280 -1240,-1280
  lines w50: -970,-1100 -970,300 ; -880,-1100 -880,300 ; -800,-1100 -800,300 ; -720,-1100 -720,1100 ; -640,-1100 -640,1100 ; -560,-1100 -560,1100 ; -480,-1100 -480,1100 ; -400,-1100 -400,1100 ; -320,-1100 -320,1100 ; -240,-1100 -240,1100 ; -160,-1100 -160,1100 ; -80,-1100 -80,1100 ; 0,-1100 0,1100 ; 80,-1100 80,1100 ; 160,-1100 160,1100 ; 240,-1100 240,1100 ; 320,-1100 320,1100 ; 400,-1100 400,1100 ; 480,-1100 480,1100 ; 560,-1100 560,1100 ; 640,-1100 640,1100 ; 720,-1100 720,1100 ; 800,-300 800,1100 ; 880,-300 880,1100 ; 960,-300 960,1100
Components Top Assy:
  lines w19.68: 0,-1550 0,-1280 ; 0,1280 0,1550 ; -1570,-1570 -1570,1570 1570,1570 1570,-1570 -1570,-1570 ; -1240,-1280 -1240,1280 1240,1280 1240,-1280 -1240,-1280
  text "'.Designator'" at -938.15,-44.83 h400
